One B-rep face of a CAD part: STEP entity #105.
In plain terms, the planar face has unit normal (-1, 0, 0).
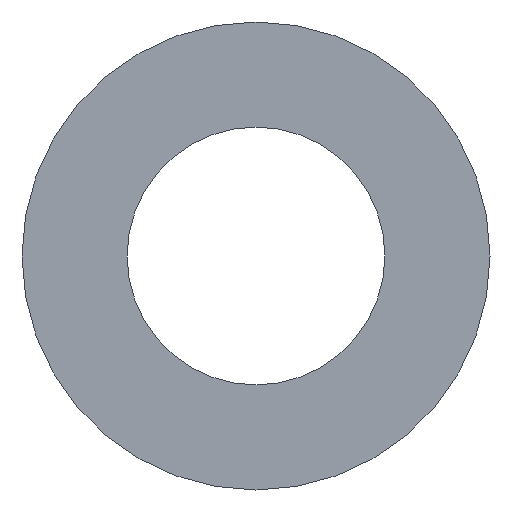
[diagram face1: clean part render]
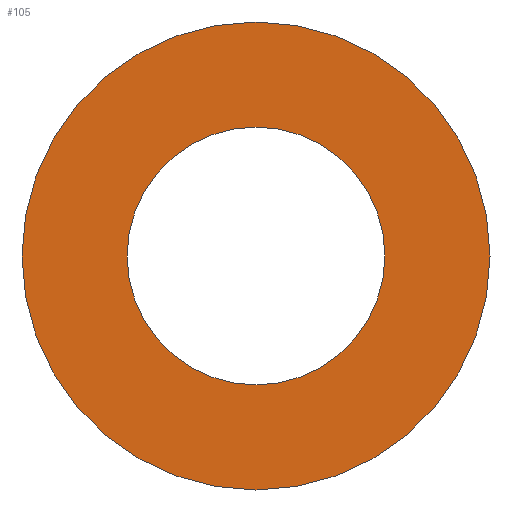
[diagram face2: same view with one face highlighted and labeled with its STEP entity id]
Its self-contained STEP definition (entity closure, numbers rounded to 3 decimals):
#21 = EDGE_CURVE('',#22,#22,#24,.T.);
#22 = VERTEX_POINT('',#23);
#23 = CARTESIAN_POINT('',(-2.,0.,-2.45));
#24 = SURFACE_CURVE('',#25,(#30,#42),.PCURVE_S1.);
#25 = CIRCLE('',#26,2.45);
#26 = AXIS2_PLACEMENT_3D('',#27,#28,#29);
#27 = CARTESIAN_POINT('',(-2.,0.,0.));
#28 = DIRECTION('',(-1.,0.,0.));
#29 = DIRECTION('',(0.,0.,-1.));
#30 = PCURVE('',#31,#36);
#31 = CYLINDRICAL_SURFACE('',#32,2.45);
#32 = AXIS2_PLACEMENT_3D('',#33,#34,#35);
#33 = CARTESIAN_POINT('',(0.,0.,0.));
#34 = DIRECTION('',(-1.,0.,0.));
#35 = DIRECTION('',(0.,0.,-1.));
#36 = DEFINITIONAL_REPRESENTATION('',(#37),#41);
#37 = LINE('',#38,#39);
#38 = CARTESIAN_POINT('',(0.,2.));
#39 = VECTOR('',#40,1.);
#40 = DIRECTION('',(1.,0.));
#41 = ( GEOMETRIC_REPRESENTATION_CONTEXT(2) 
PARAMETRIC_REPRESENTATION_CONTEXT() REPRESENTATION_CONTEXT('2D SPACE',''
  ) );
#42 = PCURVE('',#43,#48);
#43 = PLANE('',#44);
#44 = AXIS2_PLACEMENT_3D('',#45,#46,#47);
#45 = CARTESIAN_POINT('',(-2.,0.,0.));
#46 = DIRECTION('',(-1.,0.,0.));
#47 = DIRECTION('',(0.,0.,-1.));
#48 = DEFINITIONAL_REPRESENTATION('',(#49),#53);
#49 = CIRCLE('',#50,2.45);
#50 = AXIS2_PLACEMENT_2D('',#51,#52);
#51 = CARTESIAN_POINT('',(0.,0.));
#52 = DIRECTION('',(1.,0.));
#53 = ( GEOMETRIC_REPRESENTATION_CONTEXT(2) 
PARAMETRIC_REPRESENTATION_CONTEXT() REPRESENTATION_CONTEXT('2D SPACE',''
  ) );
#105 = ADVANCED_FACE('',(#106,#109),#43,.T.);
#106 = FACE_BOUND('',#107,.T.);
#107 = EDGE_LOOP('',(#108));
#108 = ORIENTED_EDGE('',*,*,#21,.T.);
#109 = FACE_BOUND('',#110,.T.);
#110 = EDGE_LOOP('',(#111));
#111 = ORIENTED_EDGE('',*,*,#112,.F.);
#112 = EDGE_CURVE('',#113,#113,#115,.T.);
#113 = VERTEX_POINT('',#114);
#114 = CARTESIAN_POINT('',(-2.,0.,-1.35));
#115 = SURFACE_CURVE('',#116,(#121,#128),.PCURVE_S1.);
#116 = CIRCLE('',#117,1.35);
#117 = AXIS2_PLACEMENT_3D('',#118,#119,#120);
#118 = CARTESIAN_POINT('',(-2.,0.,0.));
#119 = DIRECTION('',(-1.,0.,0.));
#120 = DIRECTION('',(0.,0.,-1.));
#121 = PCURVE('',#43,#122);
#122 = DEFINITIONAL_REPRESENTATION('',(#123),#127);
#123 = CIRCLE('',#124,1.35);
#124 = AXIS2_PLACEMENT_2D('',#125,#126);
#125 = CARTESIAN_POINT('',(0.,0.));
#126 = DIRECTION('',(1.,0.));
#127 = ( GEOMETRIC_REPRESENTATION_CONTEXT(2) 
PARAMETRIC_REPRESENTATION_CONTEXT() REPRESENTATION_CONTEXT('2D SPACE',''
  ) );
#128 = PCURVE('',#129,#134);
#129 = CYLINDRICAL_SURFACE('',#130,1.35);
#130 = AXIS2_PLACEMENT_3D('',#131,#132,#133);
#131 = CARTESIAN_POINT('',(0.05,0.,0.));
#132 = DIRECTION('',(-1.,0.,0.));
#133 = DIRECTION('',(0.,0.,-1.));
#134 = DEFINITIONAL_REPRESENTATION('',(#135),#139);
#135 = LINE('',#136,#137);
#136 = CARTESIAN_POINT('',(0.,2.05));
#137 = VECTOR('',#138,1.);
#138 = DIRECTION('',(1.,0.));
#139 = ( GEOMETRIC_REPRESENTATION_CONTEXT(2) 
PARAMETRIC_REPRESENTATION_CONTEXT() REPRESENTATION_CONTEXT('2D SPACE',''
  ) );
